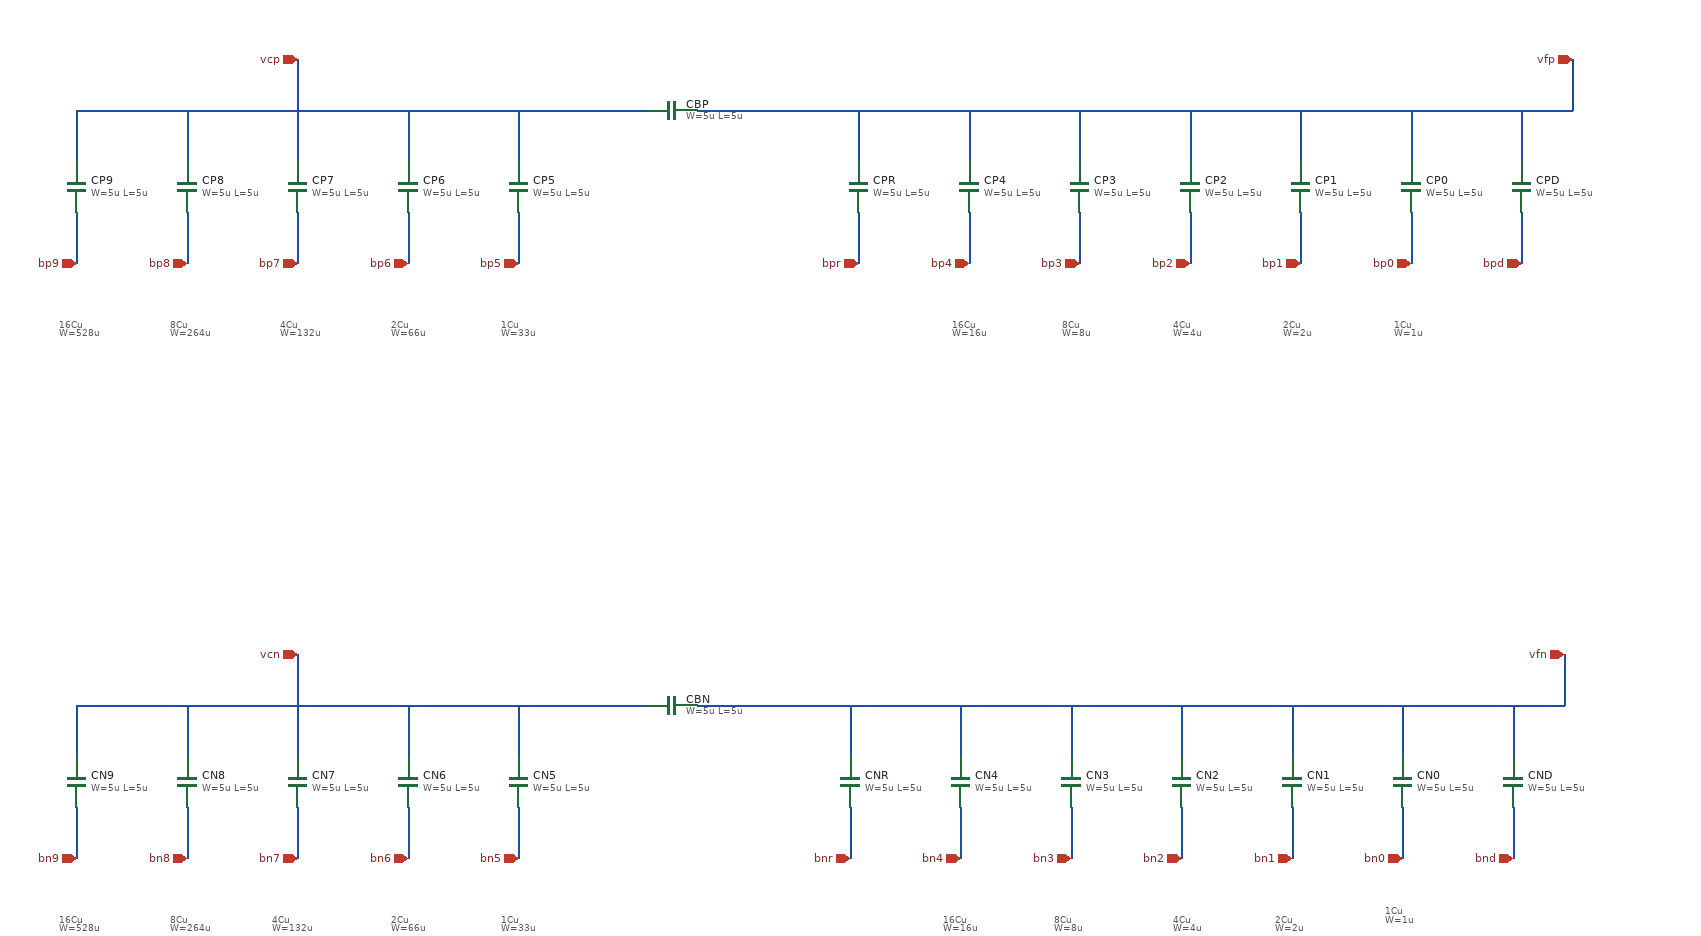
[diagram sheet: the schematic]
v {xschem version=3.4.8RC file_version=1.3}
G {}
K {}
V {}
S {}
F {}
E {}
T {16Cu
W=528u} 60 -1260 0 0 0.25 0.25 {}
T {8Cu
W=264u} 190 -1260 0 0 0.25 0.25 {}
T {4Cu
W=132u} 320 -1260 0 0 0.25 0.25 {}
T {2Cu
W=66u} 450 -1260 0 0 0.25 0.25 {}
T {1Cu
W=33u} 580 -1260 0 0 0.25 0.25 {}
T {16Cu
W=16u} 1110 -1260 0 0 0.25 0.25 {}
T {8Cu
W=8u} 1240 -1260 0 0 0.25 0.25 {}
T {4Cu
W=4u} 1370 -1260 0 0 0.25 0.25 {}
T {2Cu
W=2u} 1500 -1260 0 0 0.25 0.25 {}
T {1Cu
W=1u} 1630 -1260 0 0 0.25 0.25 {}
T {16Cu
W=528u} 60 -560 0 0 0.25 0.25 {}
T {8Cu
W=264u} 190 -560 0 0 0.25 0.25 {}
T {4Cu
W=132u} 310 -560 0 0 0.25 0.25 {}
T {2Cu
W=66u} 450 -560 0 0 0.25 0.25 {}
T {1Cu
W=33u} 580 -560 0 0 0.25 0.25 {}
T {16Cu
W=16u} 1100 -560 0 0 0.25 0.25 {}
T {8Cu
W=8u} 1230 -560 0 0 0.25 0.25 {}
T {4Cu
W=4u} 1370 -560 0 0 0.25 0.25 {}
T {2Cu
W=2u} 1490 -560 0 0 0.25 0.25 {}
T {1Cu
W=1u} 1620 -570 0 0 0.25 0.25 {}
N 80 -1500 750 -1500 {
lab=vcp}
N 870 -1500 1840 -1500 {
lab=vfp}
N 340 -1560 340 -1500 {
lab=vcp}
N 1840 -1560 1840 -1500 {
lab=vfp}
N 80 -1500 80 -1440 {
lab=vcp}
N 80 -1380 80 -1320 {
lab=bp9}
N 210 -1500 210 -1440 {
lab=vcp}
N 210 -1380 210 -1320 {
lab=bp8}
N 340 -1500 340 -1440 {
lab=vcp}
N 340 -1380 340 -1320 {
lab=bp7}
N 470 -1500 470 -1440 {
lab=vcp}
N 470 -1380 470 -1320 {
lab=bp6}
N 600 -1500 600 -1440 {
lab=vcp}
N 600 -1380 600 -1320 {
lab=bp5}
N 1000 -1500 1000 -1440 {
lab=vfp}
N 1000 -1380 1000 -1320 {
lab=bpr}
N 1130 -1500 1130 -1440 {
lab=vfp}
N 1130 -1380 1130 -1320 {
lab=bp4}
N 1260 -1500 1260 -1440 {
lab=vfp}
N 1260 -1380 1260 -1320 {
lab=bp3}
N 1390 -1500 1390 -1440 {
lab=vfp}
N 1390 -1380 1390 -1320 {
lab=bp2}
N 1520 -1500 1520 -1440 {
lab=vfp}
N 1520 -1380 1520 -1320 {
lab=bp1}
N 1650 -1500 1650 -1440 {
lab=vfp}
N 1650 -1380 1650 -1320 {
lab=bp0}
N 1780 -1500 1780 -1440 {
lab=vfp}
N 1780 -1380 1780 -1320 {
lab=bpd}
N 80 -800 750 -800 {
lab=vcn}
N 860 -800 1830 -800 {
lab=vfn}
N 340 -860 340 -800 {
lab=vcn}
N 1830 -860 1830 -800 {
lab=vfn}
N 80 -800 80 -740 {
lab=vcn}
N 80 -680 80 -620 {
lab=bn9}
N 210 -800 210 -740 {
lab=vcn}
N 210 -680 210 -620 {
lab=bn8}
N 340 -800 340 -740 {
lab=vcn}
N 340 -680 340 -620 {
lab=bn7}
N 470 -800 470 -740 {
lab=vcn}
N 470 -680 470 -620 {
lab=bn6}
N 600 -800 600 -740 {
lab=vcn}
N 600 -680 600 -620 {
lab=bn5}
N 990 -800 990 -740 {
lab=vfn}
N 990 -680 990 -620 {
lab=bnr}
N 1120 -800 1120 -740 {
lab=vfn}
N 1120 -680 1120 -620 {
lab=bn4}
N 1250 -800 1250 -740 {
lab=vfn}
N 1250 -680 1250 -620 {
lab=bn3}
N 1380 -800 1380 -740 {
lab=vfn}
N 1380 -680 1380 -620 {
lab=bn2}
N 1510 -800 1510 -740 {
lab=vfn}
N 1510 -680 1510 -620 {
lab=bn1}
N 1640 -800 1640 -740 {
lab=vfn}
N 1640 -680 1640 -620 {
lab=bn0}
N 1770 -800 1770 -740 {
lab=vfn}
N 1770 -680 1770 -620 {
lab=bnd}
N 810 -1500 870 -1500 {lab=vfp}
N 810 -800 860 -800 {lab=vfn}
C {iopin.sym} 340 -1560 3 0 {name=p_vcp lab=vcp}
C {iopin.sym} 1840 -1560 3 0 {name=p_vfp lab=vfp}
C {iopin.sym} 80 -1320 1 0 {name=p_bp9v lab=bp9}
C {symbols/cap_mim_2f0fF.sym} 80 -1410 0 0 {name=CP9
W=5u
L=5u
model=cap_mim_2f0fF
spiceprefix=X
m=16}
C {iopin.sym} 210 -1320 1 0 {name=p_bp8v lab=bp8}
C {symbols/cap_mim_2f0fF.sym} 210 -1410 0 0 {name=CP8
W=5u
L=5u
model=cap_mim_2f0fF
spiceprefix=X
m=8}
C {iopin.sym} 340 -1320 1 0 {name=p_bp7v lab=bp7}
C {symbols/cap_mim_2f0fF.sym} 340 -1410 0 0 {name=CP7
W=5u
L=5u
model=cap_mim_2f0fF
spiceprefix=X
m=4}
C {iopin.sym} 470 -1320 1 0 {name=p_bp6v lab=bp6}
C {symbols/cap_mim_2f0fF.sym} 470 -1410 0 0 {name=CP6
W=5u
L=5u
model=cap_mim_2f0fF
spiceprefix=X
m=2}
C {iopin.sym} 600 -1320 1 0 {name=p_bp5v lab=bp5}
C {symbols/cap_mim_2f0fF.sym} 600 -1410 0 0 {name=CP5
W=5u
L=5u
model=cap_mim_2f0fF
spiceprefix=X
m=1}
C {iopin.sym} 1000 -1320 1 0 {name=p_bprv lab=bpr}
C {symbols/cap_mim_2f0fF.sym} 1000 -1410 0 0 {name=CPR
W=5u
L=5u
model=cap_mim_2f0fF
spiceprefix=X
m=32}
C {iopin.sym} 1130 -1320 1 0 {name=p_bp4v lab=bp4}
C {symbols/cap_mim_2f0fF.sym} 1130 -1410 0 0 {name=CP4
W=5u
L=5u
model=cap_mim_2f0fF
spiceprefix=X
m=16}
C {iopin.sym} 1260 -1320 1 0 {name=p_bp3v lab=bp3}
C {symbols/cap_mim_2f0fF.sym} 1260 -1410 0 0 {name=CP3
W=5u
L=5u
model=cap_mim_2f0fF
spiceprefix=X
m=8}
C {iopin.sym} 1390 -1320 1 0 {name=p_bp2v lab=bp2}
C {symbols/cap_mim_2f0fF.sym} 1390 -1410 0 0 {name=CP2
W=5u
L=5u
model=cap_mim_2f0fF
spiceprefix=X
m=4}
C {iopin.sym} 1520 -1320 1 0 {name=p_bp1v lab=bp1}
C {symbols/cap_mim_2f0fF.sym} 1520 -1410 0 0 {name=CP1
W=5u
L=5u
model=cap_mim_2f0fF
spiceprefix=X
m=2}
C {iopin.sym} 1650 -1320 1 0 {name=p_bp0v lab=bp0}
C {symbols/cap_mim_2f0fF.sym} 1650 -1410 0 0 {name=CP0
W=5u
L=5u
model=cap_mim_2f0fF
spiceprefix=X
m=1}
C {iopin.sym} 1780 -1320 1 0 {name=p_bpdv lab=bpd}
C {symbols/cap_mim_2f0fF.sym} 1780 -1410 0 0 {name=CPD
W=5u
L=5u
model=cap_mim_2f0fF
spiceprefix=X
m=1}
C {symbols/cap_mim_2f0fF.sym} 780 -1500 3 0 {name=CBP
W=5u
L=5u
model=cap_mim_2f0fF
spiceprefix=X
m=2}
C {iopin.sym} 340 -860 3 0 {name=p_vcn lab=vcn}
C {iopin.sym} 1830 -860 3 0 {name=p_vfn lab=vfn}
C {iopin.sym} 80 -620 1 0 {name=p_bn9v lab=bn9}
C {symbols/cap_mim_2f0fF.sym} 80 -710 0 0 {name=CN9
W=5u
L=5u
model=cap_mim_2f0fF
spiceprefix=X
m=16}
C {iopin.sym} 210 -620 1 0 {name=p_bn8v lab=bn8}
C {symbols/cap_mim_2f0fF.sym} 210 -710 0 0 {name=CN8
W=5u
L=5u
model=cap_mim_2f0fF
spiceprefix=X
m=8}
C {iopin.sym} 340 -620 1 0 {name=p_bn7v lab=bn7}
C {symbols/cap_mim_2f0fF.sym} 340 -710 0 0 {name=CN7
W=5u
L=5u
model=cap_mim_2f0fF
spiceprefix=X
m=4}
C {iopin.sym} 470 -620 1 0 {name=p_bn6v lab=bn6}
C {symbols/cap_mim_2f0fF.sym} 470 -710 0 0 {name=CN6
W=5u
L=5u
model=cap_mim_2f0fF
spiceprefix=X
m=2}
C {iopin.sym} 600 -620 1 0 {name=p_bn5v lab=bn5}
C {symbols/cap_mim_2f0fF.sym} 600 -710 0 0 {name=CN5
W=5u
L=5u
model=cap_mim_2f0fF
spiceprefix=X
m=1}
C {iopin.sym} 990 -620 1 0 {name=p_bnrv lab=bnr}
C {symbols/cap_mim_2f0fF.sym} 990 -710 0 0 {name=CNR
W=5u
L=5u
model=cap_mim_2f0fF
spiceprefix=X
m=32}
C {iopin.sym} 1120 -620 1 0 {name=p_bn4v lab=bn4}
C {symbols/cap_mim_2f0fF.sym} 1120 -710 0 0 {name=CN4
W=5u
L=5u
model=cap_mim_2f0fF
spiceprefix=X
m=16}
C {iopin.sym} 1250 -620 1 0 {name=p_bn3v lab=bn3}
C {symbols/cap_mim_2f0fF.sym} 1250 -710 0 0 {name=CN3
W=5u
L=5u
model=cap_mim_2f0fF
spiceprefix=X
m=8}
C {iopin.sym} 1380 -620 1 0 {name=p_bn2v lab=bn2}
C {symbols/cap_mim_2f0fF.sym} 1380 -710 0 0 {name=CN2
W=5u
L=5u
model=cap_mim_2f0fF
spiceprefix=X
m=4}
C {iopin.sym} 1510 -620 1 0 {name=p_bn1v lab=bn1}
C {symbols/cap_mim_2f0fF.sym} 1510 -710 0 0 {name=CN1
W=5u
L=5u
model=cap_mim_2f0fF
spiceprefix=X
m=2}
C {iopin.sym} 1640 -620 1 0 {name=p_bn0v lab=bn0}
C {symbols/cap_mim_2f0fF.sym} 1640 -710 0 0 {name=CN0
W=5u
L=5u
model=cap_mim_2f0fF
spiceprefix=X
m=1}
C {iopin.sym} 1770 -620 1 0 {name=p_bndv lab=bnd}
C {symbols/cap_mim_2f0fF.sym} 1770 -710 0 0 {name=CND
W=5u
L=5u
model=cap_mim_2f0fF
spiceprefix=X
m=1}
C {symbols/cap_mim_2f0fF.sym} 780 -800 3 0 {name=CBN
W=5u
L=5u
model=cap_mim_2f0fF
spiceprefix=X
m=2}
C {title.sym} 160 0 0 0 {name=l1 author="Arjun Ananth"}
